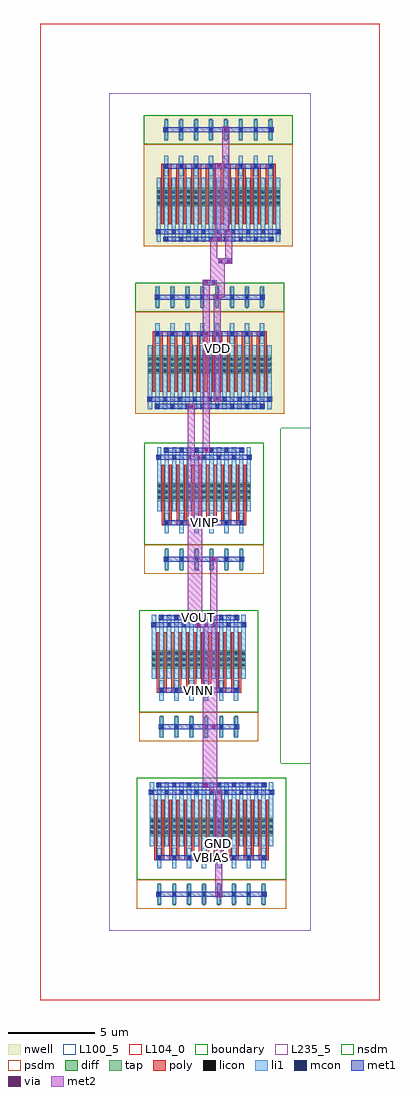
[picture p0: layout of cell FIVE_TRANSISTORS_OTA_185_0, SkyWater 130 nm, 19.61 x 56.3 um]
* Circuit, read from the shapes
.subckt FIVE_TRANSISTORS_OTA_185_0 GND VBIAS VDD VINN VINP VOUT
XM1 n1 VBIAS GND GND sky130_fd_pr__nfet_01v8 w=1.05 l=0.15 m=16
XM2 VOUT VINN n1 GND sky130_fd_pr__nfet_01v8 w=1.05 l=0.15 m=12
XM3 n2 VINP n1 GND sky130_fd_pr__nfet_01v8 w=1.05 l=0.15 m=12
XM4 VOUT n2 VDD VDD sky130_fd_pr__pfet_01v8 w=1.05 l=0.15 m=16
XM5 n2 n2 VDD VDD sky130_fd_pr__pfet_01v8 w=1.05 l=0.15 m=16
.ends

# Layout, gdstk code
from math import pi, radians
import gdstk
lib = gdstk.Library(unit=1e-6, precision=1e-09)
def R(c, l, rs):  # rectangles x0, y0, x1, y1
    for r in rs: c.add(gdstk.rectangle(r[:2], r[2:], *l))
def A(c, l, x, y, w, h, nx, ny, dx, dy):  # array of equal rectangles
    R(c, l, [(x+i*dx, y+j*dy, x+i*dx+w, y+j*dy+h) for i in range(nx) for j in range(ny)])
def P(c, l, *ps):  # polygons
    for p in ps: c.add(gdstk.Polygon(p, *l))
nwell = (64, 20)
diff = (65, 20)
tap = (65, 44)
poly = (66, 20)
licon = (66, 44)
li1 = (67, 20)
mcon = (67, 44)
met1 = (68, 20)
via = (68, 44)
met2 = (69, 20)
nsdm = (93, 44)
psdm = (94, 20)
L100_5 = (100, 5)
L104_0 = (104, 0)
boundary = (235, 4)
L235_5 = (235, 5)

dcl_pmos_s_50091844_x8_y = lib.new_cell('DCL_PMOS_S_50091844_X8_Y1_1746742421')
R(dcl_pmos_s_50091844_x8_y, nwell, [(1.99,0.84,10.59,8.4)])
R(dcl_pmos_s_50091844_x8_y, diff, [(2.725,3.15,9.855,4.2)])
A(dcl_pmos_s_50091844_x8_y, tap, 3.195, 6.915, 0.17, 1.29, 8, 1, 0.86, 0)
A(dcl_pmos_s_50091844_x8_y, poly, 2.99, 2.1, 0.15, 3.36, 16, 1, 0.43, 0)
A(dcl_pmos_s_50091844_x8_y, poly, 2.99, 5.325, 0.58, 0.27, 8, 1, 0.86, 0)
A(dcl_pmos_s_50091844_x8_y, licon, 2.765, 3.23, 0.17, 0.17, 3, 3, 0.43, 0.34)
A(dcl_pmos_s_50091844_x8_y, licon, 3.625, 3.23, 0.17, 0.17, 3, 3, 0.43, 0.34)
A(dcl_pmos_s_50091844_x8_y, licon, 4.485, 3.23, 0.17, 0.17, 3, 3, 0.43, 0.34)
A(dcl_pmos_s_50091844_x8_y, licon, 5.345, 3.23, 0.17, 0.17, 3, 3, 0.43, 0.34)
A(dcl_pmos_s_50091844_x8_y, licon, 6.205, 3.23, 0.17, 0.17, 3, 3, 0.43, 0.34)
A(dcl_pmos_s_50091844_x8_y, licon, 7.065, 3.23, 0.17, 0.17, 3, 3, 0.43, 0.34)
A(dcl_pmos_s_50091844_x8_y, licon, 7.925, 3.23, 0.17, 0.17, 3, 3, 0.43, 0.34)
A(dcl_pmos_s_50091844_x8_y, licon, 8.785, 3.23, 0.17, 0.17, 3, 3, 0.43, 0.34)
A(dcl_pmos_s_50091844_x8_y, licon, 3.195, 5.375, 0.17, 0.17, 8, 2, 0.86, 2.1)
A(dcl_pmos_s_50091844_x8_y, li1, 2.725, 1.09, 0.25, 3.7, 17, 1, 0.43, 0)
A(dcl_pmos_s_50091844_x8_y, li1, 3.155, 4.87, 0.25, 1.18, 8, 2, 0.86, 2.1)
A(dcl_pmos_s_50091844_x8_y, mcon, 3.195, 1.175, 0.17, 0.17, 8, 2, 0.86, 4.2)
A(dcl_pmos_s_50091844_x8_y, mcon, 2.765, 1.595, 0.17, 0.17, 9, 1, 0.86, 0)
A(dcl_pmos_s_50091844_x8_y, mcon, 3.195, 7.475, 0.17, 0.17, 8, 1, 0.86, 0)
R(dcl_pmos_s_50091844_x8_y, met1, [(3.11,1.12,9.47,1.4), (2.68,1.54,9.9,1.82), (3.11,5.32,9.47,5.6), (3.11,7.42,9.47,7.7)])
R(dcl_pmos_s_50091844_x8_y, via, [(6.215,1.185,6.365,1.335), (6.645,1.605,6.795,1.755), (6.215,5.385,6.365,5.535), (6.645,7.485,6.795,7.635)])
R(dcl_pmos_s_50091844_x8_y, met2, [(6.09,1.1,6.49,5.62), (6.52,1.52,6.92,7.72)])
R(dcl_pmos_s_50091844_x8_y, nsdm, [(1.99,6.72,10.59,8.4)])
R(dcl_pmos_s_50091844_x8_y, psdm, [(1.99,0.84,10.59,6.72)])
R(dcl_pmos_s_50091844_x8_y, L100_5, [(0,0,11.61,9.66)])
R(dcl_pmos_s_50091844_x8_y, boundary, [(0,0,11.61,9.66)])

nmos_s_7645620_x8_y1_174 = lib.new_cell('NMOS_S_7645620_X8_Y1_1746742424')
R(nmos_s_7645620_x8_y1_174, diff, [(2.325,3.15,9.455,4.2)])
A(nmos_s_7645620_x8_y1_174, tap, 2.795, 6.915, 0.17, 1.29, 8, 1, 0.86, 0)
A(nmos_s_7645620_x8_y1_174, poly, 2.59, 2.1, 0.15, 3.36, 16, 1, 0.43, 0)
A(nmos_s_7645620_x8_y1_174, poly, 2.59, 5.325, 0.58, 0.27, 8, 1, 0.86, 0)
A(nmos_s_7645620_x8_y1_174, licon, 2.365, 3.23, 0.17, 0.17, 3, 3, 0.43, 0.34)
A(nmos_s_7645620_x8_y1_174, licon, 3.225, 3.23, 0.17, 0.17, 3, 3, 0.43, 0.34)
A(nmos_s_7645620_x8_y1_174, licon, 4.085, 3.23, 0.17, 0.17, 3, 3, 0.43, 0.34)
A(nmos_s_7645620_x8_y1_174, licon, 4.945, 3.23, 0.17, 0.17, 3, 3, 0.43, 0.34)
A(nmos_s_7645620_x8_y1_174, licon, 5.805, 3.23, 0.17, 0.17, 3, 3, 0.43, 0.34)
A(nmos_s_7645620_x8_y1_174, licon, 6.665, 3.23, 0.17, 0.17, 3, 3, 0.43, 0.34)
A(nmos_s_7645620_x8_y1_174, licon, 7.525, 3.23, 0.17, 0.17, 3, 3, 0.43, 0.34)
A(nmos_s_7645620_x8_y1_174, licon, 8.385, 3.23, 0.17, 0.17, 3, 3, 0.43, 0.34)
A(nmos_s_7645620_x8_y1_174, licon, 2.795, 5.375, 0.17, 0.17, 8, 2, 0.86, 2.1)
A(nmos_s_7645620_x8_y1_174, li1, 2.325, 1.09, 0.25, 3.7, 17, 1, 0.43, 0)
A(nmos_s_7645620_x8_y1_174, li1, 2.755, 4.87, 0.25, 1.18, 8, 2, 0.86, 2.1)
A(nmos_s_7645620_x8_y1_174, mcon, 2.795, 1.175, 0.17, 0.17, 8, 2, 0.86, 4.2)
A(nmos_s_7645620_x8_y1_174, mcon, 2.365, 1.595, 0.17, 0.17, 9, 1, 0.86, 0)
A(nmos_s_7645620_x8_y1_174, mcon, 2.795, 7.475, 0.17, 0.17, 8, 1, 0.86, 0)
R(nmos_s_7645620_x8_y1_174, met1, [(2.71,1.12,9.07,1.4), (2.28,1.54,9.5,1.82), (2.71,5.32,9.07,5.6), (2.71,7.42,9.07,7.7)])
R(nmos_s_7645620_x8_y1_174, via, [(6.245,1.605,6.395,1.755), (6.245,7.485,6.395,7.635)])
R(nmos_s_7645620_x8_y1_174, met2, [(6.12,1.52,6.52,7.72)])
R(nmos_s_7645620_x8_y1_174, nsdm, [(1.59,0.84,10.19,6.72)])
R(nmos_s_7645620_x8_y1_174, psdm, [(1.59,6.72,10.19,8.4)])
R(nmos_s_7645620_x8_y1_174, L100_5, [(0,0,11.61,9.66)])
R(nmos_s_7645620_x8_y1_174, boundary, [(0,0,11.61,9.66)])

pmos_s_90380399_x8_y1_17 = lib.new_cell('PMOS_S_90380399_X8_Y1_1746742425')
R(pmos_s_90380399_x8_y1_17, nwell, [(1.49,0.84,10.09,8.4)])
R(pmos_s_90380399_x8_y1_17, diff, [(2.225,3.15,9.355,4.2)])
A(pmos_s_90380399_x8_y1_17, tap, 2.695, 6.915, 0.17, 1.29, 8, 1, 0.86, 0)
A(pmos_s_90380399_x8_y1_17, poly, 2.49, 2.1, 0.15, 3.36, 16, 1, 0.43, 0)
A(pmos_s_90380399_x8_y1_17, poly, 2.49, 5.325, 0.58, 0.27, 8, 1, 0.86, 0)
A(pmos_s_90380399_x8_y1_17, licon, 2.265, 3.23, 0.17, 0.17, 3, 3, 0.43, 0.34)
A(pmos_s_90380399_x8_y1_17, licon, 3.125, 3.23, 0.17, 0.17, 3, 3, 0.43, 0.34)
A(pmos_s_90380399_x8_y1_17, licon, 3.985, 3.23, 0.17, 0.17, 3, 3, 0.43, 0.34)
A(pmos_s_90380399_x8_y1_17, licon, 4.845, 3.23, 0.17, 0.17, 3, 3, 0.43, 0.34)
A(pmos_s_90380399_x8_y1_17, licon, 5.705, 3.23, 0.17, 0.17, 3, 3, 0.43, 0.34)
A(pmos_s_90380399_x8_y1_17, licon, 6.565, 3.23, 0.17, 0.17, 3, 3, 0.43, 0.34)
A(pmos_s_90380399_x8_y1_17, licon, 7.425, 3.23, 0.17, 0.17, 3, 3, 0.43, 0.34)
A(pmos_s_90380399_x8_y1_17, licon, 8.285, 3.23, 0.17, 0.17, 3, 3, 0.43, 0.34)
A(pmos_s_90380399_x8_y1_17, licon, 2.695, 5.375, 0.17, 0.17, 8, 2, 0.86, 2.1)
A(pmos_s_90380399_x8_y1_17, li1, 2.225, 1.09, 0.25, 3.7, 17, 1, 0.43, 0)
A(pmos_s_90380399_x8_y1_17, li1, 2.655, 4.87, 0.25, 1.18, 8, 2, 0.86, 2.1)
A(pmos_s_90380399_x8_y1_17, mcon, 2.695, 1.175, 0.17, 0.17, 8, 2, 0.86, 4.2)
A(pmos_s_90380399_x8_y1_17, mcon, 2.265, 1.595, 0.17, 0.17, 9, 1, 0.86, 0)
A(pmos_s_90380399_x8_y1_17, mcon, 2.695, 7.475, 0.17, 0.17, 8, 1, 0.86, 0)
R(pmos_s_90380399_x8_y1_17, met1, [(2.61,1.12,8.97,1.4), (2.18,1.54,9.4,1.82), (2.61,5.32,8.97,5.6), (2.61,7.42,8.97,7.7)])
R(pmos_s_90380399_x8_y1_17, via, [(6.145,1.605,6.295,1.755), (6.145,7.485,6.295,7.635)])
R(pmos_s_90380399_x8_y1_17, met2, [(6.02,1.52,6.42,7.72)])
R(pmos_s_90380399_x8_y1_17, nsdm, [(1.49,6.72,10.09,8.4)])
R(pmos_s_90380399_x8_y1_17, psdm, [(1.49,0.84,10.09,6.72)])
R(pmos_s_90380399_x8_y1_17, L100_5, [(0,0,11.61,9.66)])
R(pmos_s_90380399_x8_y1_17, boundary, [(0,0,11.61,9.66)])

nmos_4t_32167469_x6_y1_1 = lib.new_cell('NMOS_4T_32167469_X6_Y1_1746742422')
R(nmos_4t_32167469_x6_y1_1, diff, [(2.025,3.15,7.435,4.2)])
A(nmos_4t_32167469_x6_y1_1, tap, 2.495, 6.915, 0.17, 1.29, 6, 1, 0.86, 0)
A(nmos_4t_32167469_x6_y1_1, poly, 2.29, 2.1, 0.15, 3.36, 12, 1, 0.43, 0)
A(nmos_4t_32167469_x6_y1_1, poly, 2.29, 5.325, 0.58, 0.27, 6, 1, 0.86, 0)
A(nmos_4t_32167469_x6_y1_1, licon, 2.065, 3.23, 0.17, 0.17, 3, 3, 0.43, 0.34)
A(nmos_4t_32167469_x6_y1_1, licon, 2.925, 3.23, 0.17, 0.17, 3, 3, 0.43, 0.34)
A(nmos_4t_32167469_x6_y1_1, licon, 3.785, 3.23, 0.17, 0.17, 3, 3, 0.43, 0.34)
A(nmos_4t_32167469_x6_y1_1, licon, 4.645, 3.23, 0.17, 0.17, 3, 3, 0.43, 0.34)
A(nmos_4t_32167469_x6_y1_1, licon, 5.505, 3.23, 0.17, 0.17, 3, 3, 0.43, 0.34)
A(nmos_4t_32167469_x6_y1_1, licon, 6.365, 3.23, 0.17, 0.17, 3, 3, 0.43, 0.34)
A(nmos_4t_32167469_x6_y1_1, licon, 2.495, 5.375, 0.17, 0.17, 6, 2, 0.86, 2.1)
A(nmos_4t_32167469_x6_y1_1, li1, 2.025, 1.09, 0.25, 3.7, 13, 1, 0.43, 0)
A(nmos_4t_32167469_x6_y1_1, li1, 2.455, 4.87, 0.25, 1.18, 6, 2, 0.86, 2.1)
A(nmos_4t_32167469_x6_y1_1, mcon, 2.495, 1.175, 0.17, 0.17, 6, 2, 0.86, 4.2)
A(nmos_4t_32167469_x6_y1_1, mcon, 2.065, 1.595, 0.17, 0.17, 7, 1, 0.86, 0)
A(nmos_4t_32167469_x6_y1_1, mcon, 2.495, 7.475, 0.17, 0.17, 6, 1, 0.86, 0)
R(nmos_4t_32167469_x6_y1_1, met1, [(2.41,1.12,7.05,1.4), (1.98,1.54,7.48,1.82), (2.41,5.32,7.05,5.6), (2.41,7.42,7.05,7.7)])
R(nmos_4t_32167469_x6_y1_1, nsdm, [(1.29,0.84,8.17,6.72)])
R(nmos_4t_32167469_x6_y1_1, psdm, [(1.29,6.72,8.17,8.4)])
R(nmos_4t_32167469_x6_y1_1, L100_5, [(0,0,9.89,9.66)])
R(nmos_4t_32167469_x6_y1_1, boundary, [(0,0,9.89,9.66)])

nmos_4t_7352413_x6_y1_17 = lib.new_cell('NMOS_4T_7352413_X6_Y1_1746742423')
R(nmos_4t_7352413_x6_y1_17, diff, [(1.725,3.15,7.135,4.2)])
A(nmos_4t_7352413_x6_y1_17, tap, 2.195, 6.915, 0.17, 1.29, 6, 1, 0.86, 0)
A(nmos_4t_7352413_x6_y1_17, poly, 1.99, 2.1, 0.15, 3.36, 12, 1, 0.43, 0)
A(nmos_4t_7352413_x6_y1_17, poly, 1.99, 5.325, 0.58, 0.27, 6, 1, 0.86, 0)
A(nmos_4t_7352413_x6_y1_17, licon, 1.765, 3.23, 0.17, 0.17, 3, 3, 0.43, 0.34)
A(nmos_4t_7352413_x6_y1_17, licon, 2.625, 3.23, 0.17, 0.17, 3, 3, 0.43, 0.34)
A(nmos_4t_7352413_x6_y1_17, licon, 3.485, 3.23, 0.17, 0.17, 3, 3, 0.43, 0.34)
A(nmos_4t_7352413_x6_y1_17, licon, 4.345, 3.23, 0.17, 0.17, 3, 3, 0.43, 0.34)
A(nmos_4t_7352413_x6_y1_17, licon, 5.205, 3.23, 0.17, 0.17, 3, 3, 0.43, 0.34)
A(nmos_4t_7352413_x6_y1_17, licon, 6.065, 3.23, 0.17, 0.17, 3, 3, 0.43, 0.34)
A(nmos_4t_7352413_x6_y1_17, licon, 2.195, 5.375, 0.17, 0.17, 6, 2, 0.86, 2.1)
A(nmos_4t_7352413_x6_y1_17, li1, 1.725, 1.09, 0.25, 3.7, 13, 1, 0.43, 0)
A(nmos_4t_7352413_x6_y1_17, li1, 2.155, 4.87, 0.25, 1.18, 6, 2, 0.86, 2.1)
A(nmos_4t_7352413_x6_y1_17, mcon, 2.195, 1.175, 0.17, 0.17, 6, 2, 0.86, 4.2)
A(nmos_4t_7352413_x6_y1_17, mcon, 1.765, 1.595, 0.17, 0.17, 7, 1, 0.86, 0)
A(nmos_4t_7352413_x6_y1_17, mcon, 2.195, 7.475, 0.17, 0.17, 6, 1, 0.86, 0)
R(nmos_4t_7352413_x6_y1_17, met1, [(2.11,1.12,6.75,1.4), (1.68,1.54,7.18,1.82), (2.11,5.32,6.75,5.6), (2.11,7.42,6.75,7.7)])
R(nmos_4t_7352413_x6_y1_17, nsdm, [(0.99,0.84,7.87,6.72)])
R(nmos_4t_7352413_x6_y1_17, psdm, [(0.99,6.72,7.87,8.4)])
R(nmos_4t_7352413_x6_y1_17, L100_5, [(0,0,9.89,9.66)])
R(nmos_4t_7352413_x6_y1_17, boundary, [(0,0,9.89,9.66)])

five_transistors_ota_185 = lib.new_cell('FIVE_TRANSISTORS_OTA_185_0')
R(five_transistors_ota_185, met1, [(5.43,8.26,5.75,8.54), (5.43,8.26,5.75,8.54), (5.43,8.26,5.75,8.54), (5.43,8.26,5.75,8.54), (5.86,11.62,6.18,11.9), (5.86,11.62,6.18,11.9), (5.86,11.62,6.18,11.9), (5.86,11.62,6.18,11.9), (5,17.5,5.32,17.78), (5,17.5,5.32,17.78), (5.43,17.5,5.75,17.78), (5.43,17.5,5.75,17.78), (5.43,17.5,5.75,17.78), (5.43,17.5,5.75,17.78), (4.57,17.92,4.89,18.2), (4.57,17.92,4.89,18.2), (5.86,21.28,6.18,21.56), (5.86,21.28,6.18,21.56), (5,27.16,5.32,27.44), (5,27.16,5.32,27.44), (5.43,27.58,5.75,27.86), (5.43,27.58,5.75,27.86), (5.43,27.58,5.75,27.86), (5.43,27.58,5.75,27.86), (4.57,30.1,4.89,30.38), (4.57,30.1,4.89,30.38), (5.43,34.3,5.75,34.58), (5.43,34.3,5.75,34.58), (5.43,34.3,5.75,34.58), (5.43,34.3,5.75,34.58), (5.43,37.24,5.75,37.52), (5.43,37.24,5.75,37.52), (5.59,37.24,6.02,37.52), (5.86,37.24,6.18,37.52), (5.86,37.24,6.18,37.52), (6.29,38.5,6.61,38.78), (6.29,38.5,6.61,38.78), (6.45,38.5,6.88,38.78), (6.72,38.5,7.04,38.78), (6.72,38.5,7.04,38.78)])
P(five_transistors_ota_185, met1, [(0,0),(0,0),(0,0),(0,0)],
  [(0,0),(0,0),(0,0),(0,0)],
  [(0,0),(0,0),(0,0),(0,0)],
  [(0,0),(0,0),(0,0),(0,0)],
  [(0,0),(0,0),(0,0),(0,0)],
  [(0,0),(0,0),(0,0),(0,0)],
  [(0,0),(0,0),(0,0),(0,0)],
  [(0,0),(0,0),(0,0),(0,0)],
  [(0,0),(0,0),(0,0),(0,0)],
  [(0,0),(0,0),(0,0),(0,0)],
  [(0,0),(0,0),(0,0),(0,0)],
  [(0,0),(0,0),(0,0),(0,0)],
  [(0,0),(0,0),(0,0),(0,0)],
  [(0,0),(0,0),(0,0),(0,0)],
  [(0,0),(0,0),(0,0),(0,0)],
  [(0,0),(0,0),(0,0),(0,0)])
R(five_transistors_ota_185, via, [(5.515,8.325,5.665,8.475), (5.515,8.325,5.665,8.475), (5.515,8.325,5.665,8.475), (5.515,8.325,5.665,8.475), (5.945,11.685,6.095,11.835), (5.945,11.685,6.095,11.835), (5.945,11.685,6.095,11.835), (5.945,11.685,6.095,11.835), (5.085,17.565,5.235,17.715), (5.085,17.565,5.235,17.715), (5.515,17.565,5.665,17.715), (5.515,17.565,5.665,17.715), (5.515,17.565,5.665,17.715), (5.515,17.565,5.665,17.715), (4.655,17.985,4.805,18.135), (4.655,17.985,4.805,18.135), (5.945,21.345,6.095,21.495), (5.945,21.345,6.095,21.495), (5.085,27.225,5.235,27.375), (5.085,27.225,5.235,27.375), (5.515,27.645,5.665,27.795), (5.515,27.645,5.665,27.795), (5.515,27.645,5.665,27.795), (5.515,27.645,5.665,27.795), (4.655,30.165,4.805,30.315), (4.655,30.165,4.805,30.315), (5.515,34.365,5.665,34.515), (5.515,34.365,5.665,34.515), (5.515,34.365,5.665,34.515), (5.515,34.365,5.665,34.515), (5.515,37.305,5.665,37.455), (5.515,37.305,5.665,37.455), (5.945,37.305,6.095,37.455), (5.945,37.305,6.095,37.455), (6.375,38.565,6.525,38.715), (6.375,38.565,6.525,38.715), (6.805,38.565,6.955,38.715), (6.805,38.565,6.955,38.715)])
R(five_transistors_ota_185, met2, [(5.82,7.98,6.22,11.76), (5.39,8.24,5.79,8.56), (5.39,8.24,5.79,8.56), (5.39,8.24,5.79,8.56), (5.39,8.24,5.79,8.56), (5.39,8.4,5.79,17.64), (5.82,11.6,6.22,11.92), (5.82,11.6,6.22,11.92), (5.82,11.6,6.22,11.92), (5.82,11.6,6.22,11.92), (5.82,11.76,6.22,21.42), (4.96,17.48,5.36,17.8), (4.96,17.48,5.36,17.8), (5.39,17.48,5.79,17.8), (5.39,17.48,5.79,17.8), (5.39,17.48,5.79,17.8), (5.39,17.48,5.79,17.8), (4.96,17.64,5.36,27.3), (4.53,17.9,4.93,18.22), (4.53,17.9,4.93,18.22), (4.53,18.06,4.93,30.24), (5.82,21.26,6.22,21.58), (5.82,21.26,6.22,21.58), (4.96,27.14,5.36,27.46), (4.96,27.14,5.36,27.46), (5.39,27.56,5.79,27.88), (5.39,27.56,5.79,27.88), (5.39,27.56,5.79,27.88), (5.39,27.56,5.79,27.88), (5.39,27.72,5.79,34.44), (4.53,30.08,4.93,30.4), (4.53,30.08,4.93,30.4), (5.39,34.28,5.79,34.6), (5.39,34.28,5.79,34.6), (5.39,34.28,5.79,34.6), (5.39,34.28,5.79,34.6), (5.39,34.44,5.79,37.38), (6.25,36.54,6.65,38.64), (5.39,37.22,5.79,37.54), (5.39,37.22,5.79,37.54), (5.82,37.22,6.22,37.54), (5.82,37.22,6.22,37.54), (5.82,37.38,6.22,39.9), (6.25,38.48,6.65,38.8), (6.25,38.48,6.65,38.8), (6.68,38.48,7.08,38.8), (6.68,38.48,7.08,38.8), (6.68,38.64,7.08,40.32)])
P(five_transistors_ota_185, met2, [(0,0),(0,0),(0,0),(0,0)],
  [(0,0),(0,0),(0,0),(0,0)],
  [(0,0),(0,0),(0,0),(0,0)],
  [(0,0),(0,0),(0,0),(0,0)],
  [(0,0),(0,0),(0,0),(0,0)],
  [(0,0),(0,0),(0,0),(0,0)])
R(five_transistors_ota_185, L104_0, [(-4,-4,15.61,52.3)])
R(five_transistors_ota_185, L235_5, [(0,0,11.61,48.3)])
five_transistors_ota_185.add(gdstk.Reference(dcl_pmos_s_50091844_x8_y, (0,38.64)))
five_transistors_ota_185.add(gdstk.Reference(nmos_s_7645620_x8_y1_174, (0,9.66), x_reflection=True))
five_transistors_ota_185.add(gdstk.Reference(pmos_s_90380399_x8_y1_17, (0,28.98)))
five_transistors_ota_185.add(gdstk.Reference(nmos_4t_32167469_x6_y1_1, (9.89,19.32), rotation=pi))
five_transistors_ota_185.add(gdstk.Reference(nmos_4t_7352413_x6_y1_17, (9.89,28.98), rotation=pi))
five_transistors_ota_185.add(gdstk.Label('VDD', (6.22,33.6), layer=69, texttype=5))
five_transistors_ota_185.add(gdstk.Label('VBIAS', (5.89,4.2), layer=68, texttype=5))
five_transistors_ota_185.add(gdstk.Label('GND', (6.32,5.04), layer=69, texttype=5))
five_transistors_ota_185.add(gdstk.Label('VOUT', (5.16,18.06), layer=68, texttype=5))
five_transistors_ota_185.add(gdstk.Label('VINN', (5.16,13.86), layer=68, texttype=5))
five_transistors_ota_185.add(gdstk.Label('VINP', (5.46,23.52), layer=68, texttype=5))

lib.write_gds('FIVE_TRANSISTORS_OTA_185_0.gds')
